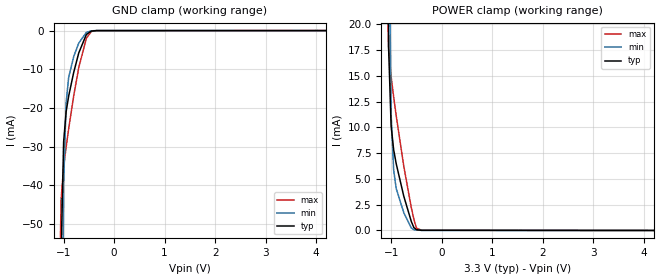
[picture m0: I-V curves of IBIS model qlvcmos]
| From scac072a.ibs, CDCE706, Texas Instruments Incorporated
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|   Model   qlvcmos
[Model]   qlvcmos
Model_type   Input
Polarity   Non-Inverting
Vinl   =   1.08V
Vinh   =   2.10V
|Variable   typ   min   max
C_comp   1.619e-12   1.613e-12   1.651e-12
|Variable   typ   min   max
[Voltage range]   3.3   3.0   3.6
|Variable   typ   min   max
[Temperature range]  55   110   -15
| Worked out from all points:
|   GND clamp passes 1 mA (typ) near -0.55 V on its own axis
|   POWER clamp passes 1 mA (typ) near -0.61 V on its own axis
[GND_clamp]
|Volts   typ   min   max
-1.2V     -6.266A    -10.23A    -3.28A
-1.1V     -212.2mA   -514.8mA   -81.05mA
-1.05V    -58.05mA   -127.1mA   -43.66mA
-1V       -28.77mA   -39.71mA   -35.23mA
-950mV    -20.93mA   -18.55mA   -30.02mA
-900mV    -16.9mA    -12.07mA   -25.35mA
-800mV    -10.78mA   -6.698mA   -16.83mA
-700mV    -5.762mA   -3.218mA   -9.538mA
-550mV    -1.017mA   -463.5uA   -1.988mA
-450mV    -128uA     -64.45uA   -224.9uA
-350mV    -9.824uA   -6.838uA   -9.952uA
4.2V      0A         0A         0A
[POWER_clamp]
|Volts   typ   min   max
-1.2V     1.548A     2.521A     817mA
-1.1V     56.08mA    128.7mA    27.64mA
-1.05V    17.73mA    32.97mA    17.7mA
-1V       10.13mA    11.26mA    14.92mA
-950mV    7.838mA    5.86mA     12.96mA
-900mV    6.492mA    4.076mA    11.15mA
-750mV    3.334mA    1.737mA    6.257mA
-600mV    865.5uA    240.4uA    2.199mA
-550mV    285.7uA    82.12uA    1.09mA
-500mV    79.68uA    43.66uA    238.3uA
-400mV    16.66uA    9.428uA    26.84uA
4.2V      0A         0A         0A
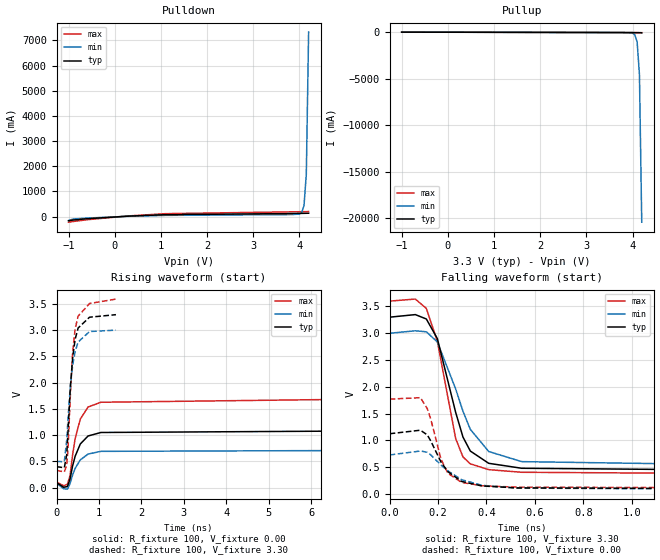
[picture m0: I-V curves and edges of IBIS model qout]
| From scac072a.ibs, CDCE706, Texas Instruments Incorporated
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|   Model   qout
[Model]   qout
Model_type   Output
Polarity   Inverting
Vmeas  =   1.50V
Cref   =   3.00pF
Rref   =   100
Vref   =   0.00V
|Variable   typ   min   max
C_comp   1.817e-12   1.811e-12   1.848e-12
|Variable   typ   min   max
[Voltage range]   3.3   3.0   3.6
|Variable   typ   min   max
[Temperature range]  55   110   -15
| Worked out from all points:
|   slope of the pulldown table from 0 to 0.495 V, typ, clamps not added: 10.2 ohm
|   slope of the pullup table from 0 to 0.495 V, typ, clamps not added: 90.6 ohm
|   rising waveform, R_fixture 100, V_fixture 0.00: 20-80 % time 289ps typ, 293ps min, 290ps max; typ from 0.095 V to 1.12 V
|   falling waveform, R_fixture 100, V_fixture 3.30: 20-80 % time 99.3ps typ, 125ps min, 83ps max; typ from 3.3 V to 0.445 V
|   rising waveform, R_fixture 100, V_fixture 3.30: 20-80 % time 151ps typ, 167ps min, 138ps max; typ from 0.399 V to 3.29 V
|   falling waveform, R_fixture 100, V_fixture 0.00: 20-80 % time 90.6ps typ, 127ps min, 67.2ps max; typ from 1.12 V to 0.101 V
[Pulldown]
|Voltage   I(typ)   I(min)   I(max)
-1V       -163.2mA   -154.4mA   -220.8mA
-900mV    -134.3mA   -95.24mA   -194.2mA
-600mV    -83.59mA   -57.17mA   -123.1mA
300mV     19.89mA    13.51mA    28.52mA
1.1V      77.05mA    49.33mA    117.9mA
3.85V     123.6mA    82.02mA    191.6mA
4V        128.1mA    102.9mA    194.9mA
4.05V     129.8mA    164.5mA    196mA
4.1V      131.6mA    439.2mA    197.2mA
4.15V     133.5mA    1.683A     199.2mA
4.2V      135.5mA    7.332A     201.4mA
[Pullup]
|Voltage   I(typ)   I(min)   I(max)
-1V       26.9mA     33.21mA    35.01mA
3.75V     -11.77mA   -16.27mA   -18.5mA
3.95V     -18.36mA   -41.93mA   -18.54mA
4V        -21.98mA   -83.71mA   -18.63mA
4.05V     -26.2mA    -257.9mA   -18.96mA
4.1V      -30.91mA   -1.033A    -19.98mA
4.15V     -36.08mA   -4.538A    -22.16mA
4.2V      -41.85mA   -20.46A    -25.62mA
[Ramp]
|Variable   typ   min   max
dV/dt_r  0.2802/1.451e-10   0.1701/1.553e-10   0.4664/1.475e-10
dV/dt_f  1.5399/1.124e-10   1.2450/1.450e-10   1.8044/9.912e-11
R_load  =  50
[Rising Waveform]
R_fixture   =   100
V_fixture   =   0.00
V_fixture_min   =   0.00
V_fixture_max   =   0.00
C_fixture   =   0.00
| Note: The rising waveform with the load to GND was simulated up to 16ns,
|   to reach the starting voltage level for the falling waveform.
|   The max. frequence of 54 MHz from the databook can be simulated.
|Time   V(typ)   V(min)   V(max)
0s        94.69mV    87.09mV    105.5mV
166.7ps   7.895mV    -20.47mV   36.23mV
257.6ps   21.7mV     -28.38mV   64.47mV
318.2ps   166.1mV    76.82mV    231.3mV
378.8ps   414.3mV    243.3mV    626.3mV
439.4ps   599.4mV    367.9mV    935.6mV
560.6ps   831.7mV    529.1mV    1.306V
742.4ps   983mV      639.4mV    1.534V
1.045ns   1.05V      691mV      1.625V
16ns      1.12V      732.1mV    1.77V
[Falling Waveform]
R_fixture   =   100
V_fixture   =   3.30
V_fixture_min   =   3.00
V_fixture_max   =   3.60
C_fixture   =   0.00
|Time   V(typ)   V(min)   V(max)
0s        3.3V       3V         3.6V
106.1ps   3.348V     3.046V     3.638V
151.5ps   3.266V     3.027V     3.463V
197ps     2.901V     2.838V     2.851V
272.7ps   1.523V     1.961V     1.035V
303ps     1.062V     1.543V     691.5mV
333.3ps   801.7mV    1.207V     563.4mV
409.1ps   573.3mV    793.4mV    454.8mV
545.5ps   480.8mV    604.7mV    406.1mV
1.5ns     445.2mV    540.4mV    379mV
[Rising Waveform]
R_fixture   =   100
V_fixture   =   3.30
V_fixture_min   =   3.00
V_fixture_max   =   3.60
C_fixture   =   0.00
|Time   V(typ)   V(min)   V(max)
0s        399.2mV    498.8mV    329.4mV
183.8ps   379.8mV    494mV      299.6mV
240.4ps   628.5mV    905.8mV    428mV
268.7ps   1.036V     1.284V     709.5mV
325.3ps   1.906V     1.938V     1.748V
381.8ps   2.491V     2.34V      2.59V
438.4ps   2.822V     2.59V      3.023V
509.1ps   3.038V     2.771V     3.263V
777.8ps   3.243V     2.97V      3.503V
1.4ns     3.291V     2.997V     3.588V
[Falling Waveform]
R_fixture   =   100
V_fixture   =   0.00
V_fixture_min   =   0.00
V_fixture_max   =   0.00
C_fixture   =   0.00
|Time   V(typ)   V(min)   V(max)
0s        1.125V     729.3mV    1.771V
127.3ps   1.191V     802.5mV    1.798V
155.6ps   1.102V     779mV      1.591V
169.7ps   991.9mV    730.8mV    1.399V
212.1ps   597.2mV    540.9mV    649.6mV
240.4ps   417.6mV    432.4mV    386.9mV
297ps     235.3mV    267.8mV    216.8mV
381.8ps   150.8mV    162.6mV    153.9mV
523.2ps   114.8mV    110.5mV    129.1mV
1.4ns     101mV      90.74mV    116.2mV
